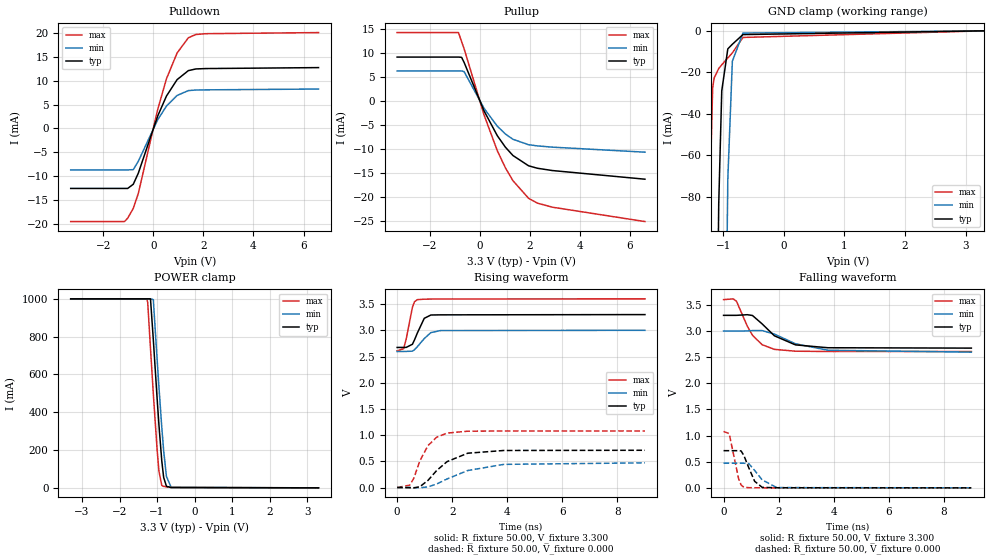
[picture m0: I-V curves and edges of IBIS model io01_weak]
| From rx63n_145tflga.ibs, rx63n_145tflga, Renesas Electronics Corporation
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[Model]   io01_weak
Model_type   I/O
Polarity   Non-Inverting
Enable   Active-High
Vinl  =   0.660V
Vinh  =   2.640V
Vmeas =   1.650V
Cref  =   30.00pF
| variable   typ   min   max
C_comp   5.910pF   5.910pF   5.910pF
| variable   typ   min   max
[Temperature Range]   45.000   105.000   -40.000
| variable   typ   min   max
[Voltage Range]   3.300V   3.000V   3.600V
| variable   typ   min   max
[Pullup Reference]   3.300V   3.000V   3.600V
| variable   typ   min   max
[Pulldown Reference]   0.000V   0.000V   0.000V
| variable   typ   min   max
[POWER Clamp Reference] 3.300V   3.000V   3.600V
| variable   typ   min   max
[GND Clamp Reference]   0.000V   0.000V   0.000V
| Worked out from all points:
|   slope of the pulldown table from 0 to 0.495 V, typ, clamps not added: 76.6 ohm
|   slope of the pullup table from 0 to 0.495 V, typ, clamps not added: 92.4 ohm
|   GND clamp passes 1 mA (typ) near -0.63 V on its own axis
|   POWER clamp passes 1 mA (typ) near -0.58 V on its own axis
|   rising waveform, R_fixture 50.00, V_fixture 3.300: 20-80 % time 304ps typ, 415ps min, 218ps max; typ from 2.67 V to 3.3 V
|   rising waveform, R_fixture 50.00, V_fixture 0.000: 20-80 % time 931ps typ, 1.4ns min, 586ps max; typ from 0 V to 0.711 V
|   falling waveform, R_fixture 50.00, V_fixture 3.300: 20-80 % time 880ps typ, 1.24ns min, 596ps max; typ from 3.3 V to 2.67 V
|   falling waveform, R_fixture 50.00, V_fixture 0.000: 20-80 % time 333ps typ, 446ps min, 237ps max; typ from 0.711 V to 0 V
[Pulldown]
| io01_weak Pulldown rx631_rx63n
| Thu Mar 22 17:15:49 2012
| voltage   I(typ)   I(min)   I(max)
-3.3V     -12.52mA   -8.65mA    -19.43mA
-1.15V    -12.52mA   -8.65mA    -19.43mA
-1.025V   -12.52mA   -8.65mA    -18.72mA
-800mV    -11.64mA   -8.594mA   -16.68mA
-600mV    -9.336mA   -6.851mA   -13.58mA
175mV     2.596mA    1.815mA    3.964mA
525mV     6.766mA    4.671mA    10.37mA
950mV     10.19mA    6.891mA    15.75mA
1.4V      12.07mA    7.901mA    18.93mA
1.7V      12.42mA    8.02mA     19.61mA
2.1V      12.5mA     8.057mA    19.78mA
6.6V      12.7mA     8.228mA    20.01mA
[Pullup]
| io01_weak Pullup rx631_rx63n
| Thu Mar 22 17:15:49 2012
| voltage   I(typ)   I(min)   I(max)
-3.3V     9.166mA    6.276mA    14.26mA
-850mV    9.166mA    6.276mA    14.26mA
-725mV    9.114mA    6.276mA    12.4mA
-625mV    8.067mA    6.148mA    10.91mA
175mV     -2.054mA   -1.515mA   -2.91mA
700mV     -7.168mA   -5.188mA   -10.28mA
1.025V    -9.573mA   -6.827mA   -13.86mA
1.325V    -11.3mA    -7.926mA   -16.53mA
1.95V     -13.44mA   -9.058mA   -20.2mA
2.3V      -13.95mA   -9.303mA   -21.2mA
2.9V      -14.43mA   -9.565mA   -22.05mA
6.6V      -16.23mA   -10.61mA   -25.04mA
[GND Clamp]
| io01_weak GNDClamp rx631_rx63n
| Thu Mar 22 17:15:49 2012
| voltage   I(typ)   I(min)   I(max)
-3.3V     -1A        -1A        -1A
-1.325V   -1A        -1A        -369.2mA
-1.3V     -928.6mA   -1A        -269.7mA
-1.25V    -694.8mA   -1A        -112.6mA
-1.175V   -376mA     -953.3mA   -27.44mA
-1.15V    -283.8mA   -837.7mA   -22.69mA
-1.075V   -83.42mA   -512.2mA   -18.16mA
-1.025V   -28.94mA   -323mA     -16.39mA
-925mV    -8.707mA   -71.38mA   -13.1mA
-850mV    -6.468mA   -14.65mA   -10.64mA
-675mV    -1.81mA    -1.082mA   -3.186mA
3.3V      0A         0A         0A
[POWER Clamp]
| io01_weak PWRClamp rx631_rx63n
| Thu Mar 22 17:15:49 2012
| voltage   I(typ)   I(min)   I(max)
-3.3V     1A         1A         1A
-1.275V   1A         1A         1A
-1.25V    1A         1A         982.1mA
-1.175V   1A         1A         736.6mA
-1.1V     784.3mA    995.9mA    498mA
-1V       476.2mA    683.1mA    204.7mA
-950mV    332.1mA    533mA      87.52mA
-875mV    143.3mA    321.7mA    12.76mA
-825mV    55.42mA    197.2mA    7.873mA
-750mV    8.12mA     59.94mA    5.513mA
-625mV    1.619mA    2.607mA    2.132mA
3.3V      0A         0A         0A
[Ramp]
dV/dt_r   0.427/931.58p  0.283/1.40n   0.648/585.98p
dV/dt_f   0.376/877.26p  0.242/1.24n   0.595/596.02p
R_load = 50.00ohm
[Rising Waveform]
| io01_weak Rising-High rx631_rx63n
| Thu Mar 22 17:15:49 2012
R_fixture = 50.00
V_fixture = 3.300
V_fixture_min = 3.000
V_fixture_max = 3.600
C_fixture = 0.00pF
| Time   V(typ)   V(min)   V(max)
0s        2.673V     2.596V     2.608V
235ps     2.673V     2.596V     2.648V
330ps     2.674V     2.597V     2.833V
555ps     2.734V     2.602V     3.439V
630ps     2.816V     2.63V      3.544V
735ps     2.949V     2.688V     3.585V
985ps     3.229V     2.842V     3.594V
1.225ns   3.292V     2.956V     3.596V
1.57ns    3.295V     2.995V     3.598V
9ns       3.3V       3V         3.6V
[Rising Waveform]
| io01_weak Rising-Low rx631_rx63n
| Thu Mar 22 17:15:49 2012
R_fixture = 50.00
V_fixture = 0.000
C_fixture = 0.00pF
| Time   V(typ)   V(min)   V(max)
0s        0V         0V         0V
460ps     -2mV       0V         46mV
605ps     -6mV       -3mV       175mV
825ps     16mV       -4mV       509mV
1.12ns    136mV      12mV       800mV
1.435ns   324mV      67mV       960mV
1.815ns   495mV      164mV      1.039V
2.565ns   655mV      325mV      1.075V
3.875ns   707mV      442mV      1.079V
9ns       711mV      471mV      1.079V
[Falling Waveform]
| io01_weak Falling-High rx631_rx63n
| Thu Mar 22 17:15:49 2012
R_fixture = 50.00
V_fixture = 3.300
V_fixture_min = 3.000
V_fixture_max = 3.600
C_fixture = 0.00pF
| Time   V(typ)   V(min)   V(max)
0s        3.3V       3V         3.6V
350ps     3.3V       3V         3.615V
470ps     3.3V       3V         3.569V
865ps     3.312V     3.001V     3.09V
1.05ns    3.297V     3.008V     2.919V
1.4ns     3.137V     3.008V     2.739V
1.845ns   2.909V     2.942V     2.649V
2.61ns    2.735V     2.756V     2.614V
3.79ns    2.68V      2.632V     2.608V
9ns       2.673V     2.596V     2.608V
[Falling Waveform]
| io01_weak Falling-Low rx631_rx63n
| Thu Mar 22 17:15:49 2012
R_fixture = 50.00
V_fixture = 0.000
C_fixture = 0.00pF
| Time   V(typ)   V(min)   V(max)
0s        711mV      471mV      1.079V
205ps     711mV      471mV      1.037V
545ps     711mV      471mV      179mV
635ps     707mV      471mV      56mV
740ps     618mV      471mV      11mV
920ps     380mV      462mV      3mV
1.13ns    125mV      333mV      2mV
1.405ns   9mV        151mV      1mV
1.935ns   2mV        5mV        0V
9ns       0V         0V         0V
